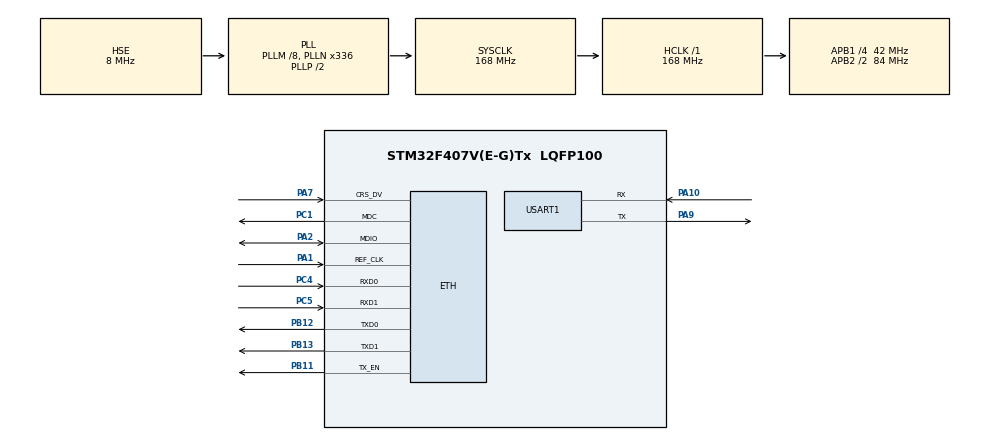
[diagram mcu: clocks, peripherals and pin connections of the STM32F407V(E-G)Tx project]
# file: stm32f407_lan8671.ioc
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ETH.MediaInterface=HAL_ETH_RMII_MODE
LWIP.BSP.number=1
LWIP.GATEWAY_ADDRESS=192.168.001.001
LWIP.IP_ADDRESS=192.168.001.110
LWIP.LWIP_DHCP=0
LWIP.NETMASK_ADDRESS=255.255.255.000
LWIP.Version=v2.1.2_Cube
LWIP0.BSP.STBoard=false
LWIP0.BSP.api=BSP_COMPONENT_DRIVER
LWIP0.BSP.component=USER_PHY
LWIP0.BSP.instance=USER_PHY
LWIP0.BSP.name=Driver_PHY
LWIP0.BSP.semaphore=S_USER_PHY
LWIP0.BSP.solution=USER_PHY
Mcu.Family=STM32F4
Mcu.Name=STM32F407V(E-G)Tx
Mcu.Package=LQFP100
NVIC.ETH_IRQn=true\:0\:0\:false\:false\:true\:true\:true\:true
NVIC.PriorityGroup=NVIC_PRIORITYGROUP_4
NVIC.USART1_IRQn=true\:0\:0\:false\:false\:true\:true\:true\:true
PA1.Mode=RMII
PA1.Signal=ETH_REF_CLK
PA10.Mode=Asynchronous
PA10.Signal=USART1_RX
PA13.Mode=Serial_Wire
PA13.Signal=SYS_JTMS-SWDIO
PA14.Mode=Serial_Wire
PA14.Signal=SYS_JTCK-SWCLK
PA2.Mode=RMII
PA2.Signal=ETH_MDIO
PA7.Mode=RMII
PA7.Signal=ETH_CRS_DV
PA9.Mode=Asynchronous
PA9.Signal=USART1_TX
PB11.Mode=RMII
PB11.Signal=ETH_TX_EN
PB12.Mode=RMII
PB12.Signal=ETH_TXD0
PB13.Mode=RMII
PB13.Signal=ETH_TXD1
PC1.Mode=RMII
PC1.Signal=ETH_MDC
PC4.Mode=RMII
PC4.Signal=ETH_RXD0
PC5.Mode=RMII
PC5.Signal=ETH_RXD1
PC9.Signal=RCC_MCO_2
PH0-OSC_IN.Mode=HSE-External-Oscillator
PH0-OSC_IN.Signal=RCC_OSC_IN
PH1-OSC_OUT.Mode=HSE-External-Oscillator
PH1-OSC_OUT.Signal=RCC_OSC_OUT
ProjectManager.HeapSize=0x400
ProjectManager.StackSize=0x800
ProjectManager.TargetToolchain=CMake
RCC.48MHZClocksFreq_Value=48000000
RCC.AHBFreq_Value=168000000
RCC.APB1CLKDivider=RCC_HCLK_DIV4
RCC.APB1Freq_Value=42000000
RCC.APB1TimFreq_Value=84000000
RCC.APB2CLKDivider=RCC_HCLK_DIV2
RCC.APB2Freq_Value=84000000
RCC.APB2TimFreq_Value=168000000
RCC.CortexFreq_Value=168000000
RCC.HCLKFreq_Value=168000000
RCC.HSE_VALUE=8000000
RCC.HSI_VALUE=16000000
RCC.LSE_VALUE=32768
RCC.PLLM=8
RCC.PLLN=336
RCC.PLLSourceVirtual=RCC_PLLSOURCE_HSE
RCC.SYSCLKFreq_VALUE=168000000
RCC.SYSCLKSource=RCC_SYSCLKSOURCE_PLLCLK
RCC.VCOOutputFreq_Value=336000000
USART1.VirtualMode=VM_ASYNC
VP_LWIP_VS_Enabled.Mode=Enabled
board=custom

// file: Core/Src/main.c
/* USER CODE BEGIN Header */
/**
  ******************************************************************************
  * @file           : main.c
  * @brief          : Main program body
  ******************************************************************************
  * @attention
  *
  * Copyright (c) 2026 STMicroelectronics.
  * All rights reserved.
  *
  * This software is licensed under terms that can be found in the LICENSE file
  * in the root directory of this software component.
  * If no LICENSE file comes with this software, it is provided AS-IS.
  *
  ******************************************************************************
  */
/* USER CODE END Header */
#include "main.h"
#include "app_network.h"
#include "lwip.h"

UART_HandleTypeDef huart1;

void SystemClock_Config(void);
static void MX_GPIO_Init(void);
static void MX_USART1_UART_Init(void);
/* USER CODE BEGIN PFP */
static void ConfigureRmiiReferenceClockOutput(void);

/* USER CODE END PFP */

/* USER CODE BEGIN 0 */

static void ConfigureRmiiReferenceClockOutput(void)
{
  RCC_PeriphCLKInitTypeDef periph_clk_init = {0};

  periph_clk_init.PeriphClockSelection = RCC_PERIPHCLK_PLLI2S;
  periph_clk_init.PLLI2S.PLLI2SN = 100;
  periph_clk_init.PLLI2S.PLLI2SR = 2;

  if (HAL_RCCEx_PeriphCLKConfig(&periph_clk_init) != HAL_OK)
  {
    Error_Handler();
  }

  HAL_RCC_MCOConfig(RCC_MCO2, RCC_MCO2SOURCE_PLLI2SCLK, RCC_MCODIV_1);
}

/* USER CODE END 0 */

int main(void)
{

  /* MCU Configuration--------------------------------------------------------*/

  /* Reset of all peripherals, Initializes the Flash interface and the Systick. */
  HAL_Init();

  /* Configure the system clock */
  SystemClock_Config();

  /* USER CODE BEGIN SysInit */

  ConfigureRmiiReferenceClockOutput();

  /* USER CODE END SysInit */

  /* Initialize all configured peripherals */
  MX_GPIO_Init();
  MX_USART1_UART_Init();
  App_Network_SetUart(&huart1);

  HAL_Delay(10);
  HAL_GPIO_WritePin(LAN8671_RESET_N_GPIO_Port, LAN8671_RESET_N_Pin, GPIO_PIN_SET);
  HAL_Delay(100);

  HAL_Delay(300);
  /* USER CODE BEGIN 2 */

  MX_LWIP_Init();
  debug_printf("\r\nSTM32F407 + LAN8671 startup\r\n");
  App_Network_Init();
  App_Network_OnLinkStatusChanged(&gnetif);

  /* USER CODE END 2 */

  /* Infinite loop */
  while (1)
  {

    /* USER CODE BEGIN 3 */
    MX_LWIP_Process();
  }
  /* USER CODE END 3 */
}

void SystemClock_Config(void)
{
  RCC_OscInitTypeDef RCC_OscInitStruct = {0};
  RCC_ClkInitTypeDef RCC_ClkInitStruct = {0};

  /** Configure the main internal regulator output voltage
  */
  __HAL_RCC_PWR_CLK_ENABLE();
  __HAL_PWR_VOLTAGESCALING_CONFIG(PWR_REGULATOR_VOLTAGE_SCALE1);

  /** Initializes the RCC Oscillators according to the specified parameters
  * in the RCC_OscInitTypeDef structure.
  */
  RCC_OscInitStruct.OscillatorType = RCC_OSCILLATORTYPE_HSE;
  RCC_OscInitStruct.HSEState = RCC_HSE_ON;
  RCC_OscInitStruct.PLL.PLLState = RCC_PLL_ON;
  RCC_OscInitStruct.PLL.PLLSource = RCC_PLLSOURCE_HSE;
  RCC_OscInitStruct.PLL.PLLM = 8;
  RCC_OscInitStruct.PLL.PLLN = 336;
  RCC_OscInitStruct.PLL.PLLP = RCC_PLLP_DIV2;
  RCC_OscInitStruct.PLL.PLLQ = 7;
  if (HAL_RCC_OscConfig(&RCC_OscInitStruct) != HAL_OK)
  {
    Error_Handler();
  }

  /** Initializes the CPU, AHB and APB buses clocks
  */
  RCC_ClkInitStruct.ClockType = RCC_CLOCKTYPE_HCLK|RCC_CLOCKTYPE_SYSCLK
                              |RCC_CLOCKTYPE_PCLK1|RCC_CLOCKTYPE_PCLK2;
  RCC_ClkInitStruct.SYSCLKSource = RCC_SYSCLKSOURCE_PLLCLK;
  RCC_ClkInitStruct.AHBCLKDivider = RCC_SYSCLK_DIV1;
  RCC_ClkInitStruct.APB1CLKDivider = RCC_HCLK_DIV4;
  RCC_ClkInitStruct.APB2CLKDivider = RCC_HCLK_DIV2;

  if (HAL_RCC_ClockConfig(&RCC_ClkInitStruct, FLASH_LATENCY_5) != HAL_OK)
  {
    Error_Handler();
  }
}

static void MX_USART1_UART_Init(void)
{

  huart1.Instance = USART1;
  huart1.Init.BaudRate = 115200;
  huart1.Init.WordLength = UART_WORDLENGTH_8B;
  huart1.Init.StopBits = UART_STOPBITS_1;
  huart1.Init.Parity = UART_PARITY_NONE;
  huart1.Init.Mode = UART_MODE_TX_RX;
  huart1.Init.HwFlowCtl = UART_HWCONTROL_NONE;
  huart1.Init.OverSampling = UART_OVERSAMPLING_16;
  if (HAL_UART_Init(&huart1) != HAL_OK)
  {
    Error_Handler();
  }

}

static void MX_GPIO_Init(void)
{
  GPIO_InitTypeDef GPIO_InitStruct = {0};

  /* GPIO Ports Clock Enable */
  __HAL_RCC_GPIOH_CLK_ENABLE();
  __HAL_RCC_GPIOC_CLK_ENABLE();
  __HAL_RCC_GPIOA_CLK_ENABLE();
  __HAL_RCC_GPIOB_CLK_ENABLE();

  HAL_GPIO_WritePin(LAN8671_RESET_N_GPIO_Port, LAN8671_RESET_N_Pin, GPIO_PIN_RESET);

  GPIO_InitStruct.Pin = LAN8671_RESET_N_Pin;
  GPIO_InitStruct.Mode = GPIO_MODE_OUTPUT_PP;
  GPIO_InitStruct.Pull = GPIO_NOPULL;
  GPIO_InitStruct.Speed = GPIO_SPEED_FREQ_LOW;
  HAL_GPIO_Init(LAN8671_RESET_N_GPIO_Port, &GPIO_InitStruct);

  GPIO_InitStruct.Pin = LAN8671_IRQ_N_Pin;
  GPIO_InitStruct.Mode = GPIO_MODE_INPUT;
  GPIO_InitStruct.Pull = GPIO_PULLUP;
  HAL_GPIO_Init(LAN8671_IRQ_N_GPIO_Port, &GPIO_InitStruct);

}

void Error_Handler(void)
{
  __disable_irq();
  while (1)
  {
  }
}
